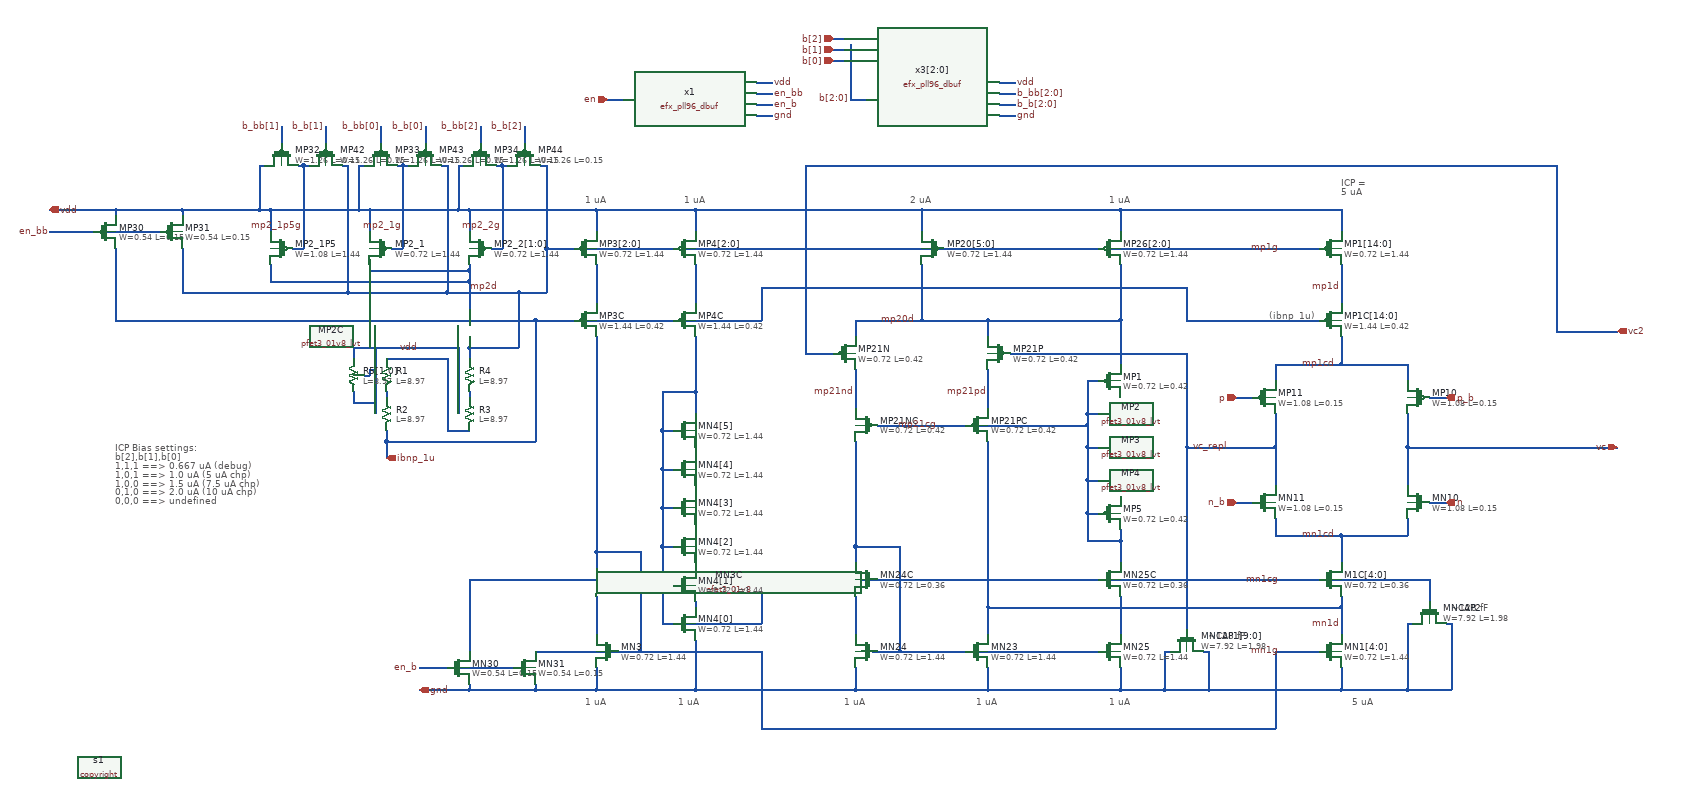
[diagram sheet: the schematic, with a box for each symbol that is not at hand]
v {xschem version=3.4.7 file_version=1.2}
G {}
K {}
V {}
S {}
E {}
T {ICP =
5 uA} 2250 -1060 0 1 0.4 0.4 {hcenter=true}
T {1 uA} 880 -120 0 0 0.4 0.4 {}
T {5 uA} 2270 -120 0 1 0.4 0.4 {}
T {ICP Bias settings:
b[2],b[1],b[0]
1,1,1 ==> 0.667 uA (debug)
1,0,1 ==> 1.0 uA (5 uA chp)
1,0,0 ==> 1.5 uA (7.5 uA chp)
0,1,0 ==> 2.0 uA (10 uA chp)
0,0,0 ==> undefined} 30 -580 0 0 0.4 0.4 {}
T {2 uA} 1470 -1030 0 0 0.4 0.4 {}
T {1 uA} 1590 -120 0 0 0.4 0.4 {}
T {1 uA} 1350 -120 0 0 0.4 0.4 {}
T {1 uA} 880 -1030 0 0 0.4 0.4 {}
T {(ibnp_1u)} 2120 -820 0 0 0.3 0.3 {hcenter=true}
T {1 uA} 1060 -1030 0 0 0.4 0.4 {}
T {1 uA} 1050 -120 0 0 0.4 0.4 {}
T {1 uA} 1830 -120 0 0 0.4 0.4 {}
T {1 uA} 1830 -1030 0 0 0.4 0.4 {}
T {~128 fF} 2010 -240 0 0 0.3 0.3 {}
T {~128 fF} 2450 -290 0 0 0.3 0.3 {}
N 900 -170 900 -130 {lab=gnd}
N 900 -300 900 -230 {lab=#net1}
N 2250 -900 2250 -830 {lab=mp1d}
N 2250 -1000 2250 -960 {lab=vdd}
N 2250 -170 2250 -130 {lab=gnd}
N 2250 -280 2250 -230 {lab=mn1d}
N 2250 -770 2250 -720 {lab=mp1cd}
N 2250 -410 2250 -360 {lab=mn1cd}
N 2130 -410 2250 -410 {lab=mn1cd}
N 2250 -410 2370 -410 {lab=mn1cd}
N 2250 -720 2370 -720 {lab=mp1cd}
N 2130 -720 2250 -720 {lab=mp1cd}
N 2130 -720 2130 -690 {lab=mp1cd}
N 2130 -440 2130 -410 {lab=mn1cd}
N 2370 -440 2370 -410 {lab=mn1cd}
N 2370 -720 2370 -690 {lab=mp1cd}
N 2410 -470 2440 -470 {lab=n}
N 2060 -660 2090 -660 {lab=p}
N 2060 -470 2090 -470 {lab=n_b}
N 1490 -1000 1490 -960 {
lab=vdd}
N 920 -1200 950 -1200 {
lab=en}
N 670 -140 670 -130 {
lab=gnd}
N 150 -1000 150 -990 {
lab=vdd}
N 30 -1000 30 -990 {
lab=vdd}
N 2410 -660 2440 -660 {
lab=p_b}
N 790 -140 790 -130 {
lab=gnd}
N 1610 -800 1610 -770 {lab=mp20d}
N 1370 -800 1370 -770 {lab=mp20d}
N 1370 -800 1490 -800 {lab=mp20d}
N 1490 -900 1490 -800 {
lab=mp20d}
N 1610 -170 1610 -130 {
lab=gnd}
N 1370 -170 1370 -130 {
lab=gnd}
N 1370 -300 1370 -230 {
lab=#net2}
N 1370 -390 1450 -390 {
lab=#net3}
N 1450 -390 1450 -200 {
lab=#net3}
N 900 -380 900 -350 {lab=mn1g}
N 670 -130 790 -130 {
lab=gnd}
N 1280 -740 1330 -740 {
lab=vc2}
N 670 -1000 670 -960 {lab=vdd}
N 490 -1000 490 -960 {lab=vdd}
N 470 -1080 470 -1000 {
lab=vdd}
N 550 -1080 560 -1080 {
lab=mp2_1g}
N 550 -1080 550 -930 {
lab=mp2_1g}
N 530 -930 550 -930 {
lab=mp2_1g}
N 630 -1080 630 -850 {
lab=mp1g}
N 620 -1080 630 -1080 {
lab=mp1g}
N 470 -1080 480 -1080 {
lab=vdd}
N 310 -1000 310 -960 {lab=vdd}
N 290 -1080 290 -1000 {
lab=vdd}
N 370 -1080 380 -1080 {
lab=mp2_1p5g}
N 370 -1080 370 -930 {
lab=mp2_1p5g}
N 350 -930 370 -930 {
lab=mp2_1p5g}
N 440 -1080 450 -1080 {
lab=mp1g}
N 290 -1080 300 -1080 {
lab=vdd}
N 470 -1000 490 -1000 {
lab=vdd}
N 310 -900 310 -870 {
lab=mp2d}
N 710 -930 730 -930 {
lab=mp2_2g}
N 540 -1080 550 -1080 {
lab=mp2_1g}
N 290 -1000 310 -1000 {
lab=vdd}
N 360 -1080 370 -1080 {
lab=mp2_1p5g}
N 900 -1000 900 -960 {
lab=vdd}
N 900 -900 900 -830 {
lab=#net4}
N 150 -1000 290 -1000 {
lab=vdd}
N 580 -130 670 -130 {
lab=gnd}
N 670 -330 670 -200 {
lab=mn1cg}
N 580 -170 750 -170 {
lab=en_b}
N 30 -1000 150 -1000 {
lab=vdd}
N -90 -1000 30 -1000 {
lab=vdd}
N -90 -960 110 -960 {
lab=en_bb}
N 330 -1150 330 -1120 {
lab=b_bb[1]}
N 410 -1150 410 -1120 {
lab=b_b[1]}
N 510 -1150 510 -1120 {
lab=b_bb[0]}
N 590 -1150 590 -1120 {
lab=b_b[0]}
N 1190 -1230 1220 -1230 {
lab=vdd}
N 1190 -1210 1220 -1210 {
lab=en_bb}
N 1190 -1190 1220 -1190 {
lab=en_b}
N 1190 -1170 1220 -1170 {
lab=gnd}
N 1360 -1200 1390 -1200 {
lab=b[2:0]}
N 1630 -1230 1660 -1230 {
lab=vdd}
N 1630 -1210 1660 -1210 {
lab=b_bb[2:0]}
N 1630 -1190 1660 -1190 {
lab=b_b[2:0]}
N 1630 -1170 1660 -1170 {
lab=gnd}
N 670 -770 670 -750 {
lab=mp1g}
N 760 -850 760 -750 {
lab=mp1g}
N 30 -930 30 -800 {
lab=ibnp_1u}
N 670 -750 670 -730 {
lab=mp1g}
N 900 -380 980 -380 {
lab=mn1g}
N 980 -380 980 -200 {
lab=mn1g}
N 790 -130 900 -130 {
lab=gnd}
N 310 -1000 470 -1000 {
lab=vdd}
N 670 -750 760 -750 {
lab=mp1g}
N 650 -1000 670 -1000 {
lab=vdd}
N 670 -870 670 -820 {
lab=mp2d}
N 450 -850 630 -850 {
lab=mp1g}
N 150 -850 450 -850 {
lab=mp1g}
N 450 -1080 450 -850 {
lab=mp1g}
N 490 -910 490 -890 {
lab=mp2d}
N 490 -890 670 -890 {
lab=mp2d}
N 670 -900 670 -890 {
lab=mp2d}
N 310 -870 670 -870 {
lab=mp2d}
N 670 -890 670 -870 {
lab=mp2d}
N 150 -930 150 -850 {
lab=mp1g}
N 670 -670 670 -660 {
lab=#net5}
N 520 -670 520 -660 {
lab=#net6}
N 520 -730 630 -730 {
lab=#net7}
N 650 -750 650 -630 {
lab=vdd}
N 500 -650 500 -630 {
lab=vdd}
N 630 -600 670 -600 {
lab=#net7}
N 520 -580 790 -580 {
lab=ibnp_1u}
N 520 -580 520 -550 {
lab=ibnp_1u}
N 460 -750 460 -730 {
lab=vdd}
N 500 -750 650 -750 {
lab=vdd}
N 460 -750 500 -750 {
lab=vdd}
N 500 -710 500 -650 {
lab=vdd}
N 460 -670 460 -650 {
lab=vdd}
N 460 -650 500 -650 {
lab=vdd}
N 630 -730 630 -600 {
lab=#net7}
N 520 -600 520 -580 {
lab=ibnp_1u}
N 790 -800 790 -580 {
lab=ibnp_1u}
N 650 -1080 650 -1000 {
lab=vdd}
N 730 -1080 740 -1080 {
lab=mp2_2g}
N 730 -1080 730 -930 {
lab=mp2_2g}
N 800 -1080 810 -1080 {
lab=mp1g}
N 650 -1080 660 -1080 {
lab=vdd}
N 720 -1080 730 -1080 {
lab=mp2_2g}
N 690 -1150 690 -1120 {
lab=b_bb[2]}
N 770 -1150 770 -1120 {
lab=b_b[2]}
N 490 -1000 650 -1000 {
lab=vdd}
N 630 -850 760 -850 {
lab=mp1g}
N 810 -930 810 -850 {
lab=mp1g}
N 810 -1080 810 -930 {
lab=mp1g}
N 760 -850 810 -850 {
lab=mp1g}
N 30 -800 790 -800 {
lab=ibnp_1u}
N 1330 -1310 1350 -1310 {
lab=b[2]}
N 1330 -1290 1350 -1290 {
lab=b[1]}
N 1330 -1270 1350 -1270 {
lab=b[0]}
N 1360 -1300 1360 -1200 {
lab=b[2:0]}
N 480 -700 490 -700 {
lab=vdd}
N 490 -710 490 -700 {
lab=vdd}
N 490 -710 500 -710 {
lab=vdd}
N 500 -750 500 -710 {
lab=vdd}
N 900 -770 900 -380 {
lab=mn1g}
N 1080 -1000 1080 -960 {
lab=vdd}
N 1080 -900 1080 -830 {
lab=#net8}
N 900 -1000 1080 -1000 {
lab=vdd}
N 670 -1000 900 -1000 {
lab=vdd}
N 1020 -320 1020 -250 {
lab=mn1cg}
N 1020 -460 1040 -460 {
lab=mn1cg}
N 1020 -390 1040 -390 {
lab=mn1cg}
N 1020 -460 1020 -390 {
lab=mn1cg}
N 1020 -320 1040 -320 {
lab=mn1cg}
N 1020 -390 1020 -320 {
lab=mn1cg}
N 1080 -430 1080 -420 {
lab=#net9}
N 1080 -360 1080 -350 {
lab=#net10}
N 1080 -290 1080 -280 {
lab=#net11}
N 1020 -530 1040 -530 {
lab=mn1cg}
N 1080 -500 1080 -490 {
lab=#net12}
N 1020 -530 1020 -460 {
lab=mn1cg}
N 2370 -570 2370 -500 {lab=vc}
N 2370 -630 2370 -570 {lab=vc}
N 2370 -570 2750 -570 {
lab=vc}
N 2130 -200 2210 -200 {
lab=mn1g}
N 790 -800 1200 -800 {
lab=ibnp_1u}
N 1200 -860 1200 -800 {
lab=ibnp_1u}
N 1370 -390 1370 -360 {
lab=#net3}
N 1200 -860 1970 -860 {
lab=ibnp_1u}
N 1850 -800 1850 -720 {lab=mp20d}
N 1080 -1000 1490 -1000 {
lab=vdd}
N 1850 -1000 1850 -960 {
lab=vdd}
N 1490 -1000 1850 -1000 {
lab=vdd}
N 1370 -130 1610 -130 {
lab=gnd}
N 1850 -170 1850 -130 {
lab=gnd}
N 1850 -300 1850 -230 {
lab=#net13}
N 1400 -200 1450 -200 {
lab=#net3}
N 790 -200 980 -200 {
lab=mn1g}
N 980 -200 1200 -200 {
lab=mn1g}
N 1490 -800 1610 -800 {
lab=mp20d}
N 1200 -200 1200 -60 {
lab=mn1g}
N 2130 -200 2130 -60 {
lab=mn1g}
N 1020 -600 1040 -600 {
lab=mn1cg}
N 1080 -570 1080 -560 {
lab=#net14}
N 1020 -600 1020 -530 {
lab=mn1cg}
N 1080 -670 1080 -620 {
lab=mn1cg}
N 1080 -220 1080 -130 {
lab=gnd}
N 900 -130 1080 -130 {
lab=gnd}
N 1020 -670 1020 -600 {
lab=mn1cg}
N 1020 -670 1080 -670 {
lab=mn1cg}
N 1080 -770 1080 -670 {
lab=mn1cg}
N 1020 -250 1200 -250 {
lab=mn1cg}
N 1200 -330 1200 -250 {
lab=mn1cg}
N 670 -330 1200 -330 {
lab=mn1cg}
N 810 -930 2210 -930 {
lab=mp1g}
N 2130 -570 2130 -500 {
lab=vc_repl}
N 1200 -60 2130 -60 {
lab=mn1g}
N 1930 -200 1940 -200 {
lab=gnd}
N 2000 -200 2010 -200 {
lab=gnd}
N 1930 -130 2010 -130 {
lab=gnd}
N 2370 -250 2380 -250 {
lab=gnd}
N 2370 -250 2370 -130 {
lab=gnd}
N 2440 -250 2450 -250 {
lab=gnd}
N 2450 -250 2450 -130 {
lab=gnd}
N 2370 -130 2450 -130 {
lab=gnd}
N 2410 -330 2410 -290 {
lab=mn1cg}
N 2250 -130 2370 -130 {
lab=gnd}
N 2010 -130 2250 -130 {
lab=gnd}
N 1970 -800 2210 -800 {
lab=ibnp_1u}
N 1970 -570 2130 -570 {
lab=vc_repl}
N 2130 -630 2130 -570 {
lab=vc_repl}
N 1080 -130 1370 -130 {
lab=gnd}
N 2640 -1080 2640 -780 {lab=vc2}
N 2640 -780 2750 -780 {lab=vc2}
N 1610 -130 1850 -130 {
lab=gnd}
N 1970 -740 1970 -570 {lab=vc_repl}
N 1280 -1080 1280 -740 {lab=vc2}
N 1280 -1080 2640 -1080 {lab=vc2}
N 1610 -280 2250 -280 {lab=mn1d}
N 1610 -280 1610 -230 {lab=mn1d}
N 2250 -300 2250 -280 {lab=mn1d}
N 1790 -450 1790 -400 {lab=mp21cg}
N 1850 -420 1850 -400 {lab=mp21cg}
N 1200 -330 2410 -330 {
lab=mn1cg}
N 1850 -1000 2250 -1000 {
lab=vdd}
N 1850 -130 1930 -130 {
lab=gnd}
N 1790 -400 1850 -400 {lab=mp21cg}
N 1790 -690 1810 -690 {lab=mp21cg}
N 1790 -630 1810 -630 {lab=mp21cg}
N 1790 -690 1790 -630 {lab=mp21cg}
N 1790 -570 1810 -570 {lab=mp21cg}
N 1790 -610 1790 -570 {lab=mp21cg}
N 1790 -510 1810 -510 {lab=mp21cg}
N 1790 -570 1790 -510 {lab=mp21cg}
N 1790 -450 1810 -450 {lab=mp21cg}
N 1790 -510 1790 -450 {lab=mp21cg}
N 1650 -740 1970 -740 {
lab=vc_repl}
N 1450 -200 1810 -200 {
lab=#net3}
N 1850 -400 1850 -360 {lab=mp21cg}
N 1930 -200 1930 -130 {
lab=gnd}
N 2010 -200 2010 -130 {
lab=gnd}
N 1970 -570 1970 -240 {lab=vc_repl}
N 1970 -860 1970 -800 {lab=ibnp_1u}
N 1610 -800 1850 -800 {lab=mp20d}
N 1850 -900 1850 -800 {lab=mp20d}
N 1370 -710 1370 -640 {
lab=mp21nd}
N 1610 -710 1610 -640 {
lab=mp21pd}
N 1370 -580 1370 -390 {lab=#net3}
N 1610 -580 1610 -280 {lab=mn1d}
N 1790 -630 1790 -610 {lab=mp21cg}
N 1410 -610 1790 -610 {lab=mp21cg}
C {title_efx.sym} 200 -40 0 0 {name=l1 author="ejfogleman"}
C {iopin.sym} -90 -1000 0 1 {name=p1 lab=vdd}
C {iopin.sym} 580 -130 0 1 {name=p2 lab=gnd}
C {iopin.sym} 520 -550 3 1 {name=p3 lab=ibnp_1u
}
C {sky130_fd_pr/pfet3_01v8_lvt.sym} 690 -930 0 1 {name=MP2_2[1:0]
W=0.72
L=1.44
body=vdd
nf=1
mult=1
ad="'int((nf+1)/2) * W/nf * 0.29'" 
pd="'2*int((nf+1)/2) * (W/nf + 0.29)'"
as="'int((nf+2)/2) * W/nf * 0.29'" 
ps="'2*int((nf+2)/2) * (W/nf + 0.29)'"
nrd="'0.29 / W'" nrs="'0.29 / W'"
sa=0 sb=0 sd=0
model=pfet_01v8_lvt
spiceprefix=X
}
C {sky130_fd_pr/nfet3_01v8.sym} 920 -200 0 1 {name=MN3
W=0.72
L=1.44
body=gnd
nf=1
mult=1
ad="'int((nf+1)/2) * W/nf * 0.29'" 
pd="'2*int((nf+1)/2) * (W/nf + 0.29)'"
as="'int((nf+2)/2) * W/nf * 0.29'" 
ps="'2*int((nf+2)/2) * (W/nf + 0.29)'"
nrd="'0.29 / W'" nrs="'0.29 / W'"
sa=0 sb=0 sd=0
model=nfet_01v8
spiceprefix=X
}
C {sky130_fd_pr/nfet3_01v8.sym} 920 -330 0 1 {name=MN3C
W=0.72
L=0.36
body=gnd
nf=1
mult=1
ad="'int((nf+1)/2) * W/nf * 0.29'" 
pd="'2*int((nf+1)/2) * (W/nf + 0.29)'"
as="'int((nf+2)/2) * W/nf * 0.29'" 
ps="'2*int((nf+2)/2) * (W/nf + 0.29)'"
nrd="'0.29 / W'" nrs="'0.29 / W'"
sa=0 sb=0 sd=0
model=nfet_01v8
spiceprefix=X
}
C {sky130_fd_pr/pfet3_01v8_lvt.sym} 2230 -930 0 0 {name=MP1[14:0]
W=0.72
L=1.44
body=vdd
nf=1
mult=1
ad="'int((nf+1)/2) * W/nf * 0.29'" 
pd="'2*int((nf+1)/2) * (W/nf + 0.29)'"
as="'int((nf+2)/2) * W/nf * 0.29'" 
ps="'2*int((nf+2)/2) * (W/nf + 0.29)'"
nrd="'0.29 / W'" nrs="'0.29 / W'"
sa=0 sb=0 sd=0
model=pfet_01v8_lvt
spiceprefix=X
}
C {sky130_fd_pr/pfet3_01v8_lvt.sym} 690 -800 0 1 {name=MP2C
W=1.44
L=0.42
body=vdd
nf=2
mult=1
ad="'int((nf+1)/2) * W/nf * 0.29'" 
pd="'2*int((nf+1)/2) * (W/nf + 0.29)'"
as="'int((nf+2)/2) * W/nf * 0.29'" 
ps="'2*int((nf+2)/2) * (W/nf + 0.29)'"
nrd="'0.29 / W'" nrs="'0.29 / W'"
sa=0 sb=0 sd=0
model=pfet_01v8_lvt
spiceprefix=X
}
C {sky130_fd_pr/pfet3_01v8_lvt.sym} 2230 -800 0 0 {name=MP1C[14:0]
W=1.44
L=0.42
body=vdd
nf=2
mult=1
ad="'int((nf+1)/2) * W/nf * 0.29'" 
pd="'2*int((nf+1)/2) * (W/nf + 0.29)'"
as="'int((nf+2)/2) * W/nf * 0.29'" 
ps="'2*int((nf+2)/2) * (W/nf + 0.29)'"
nrd="'0.29 / W'" nrs="'0.29 / W'"
sa=0 sb=0 sd=0
model=pfet_01v8_lvt
spiceprefix=X
}
C {sky130_fd_pr/nfet3_01v8.sym} 2230 -200 0 0 {name=MN1[4:0]
W=0.72
L=1.44
body=gnd
nf=1
mult=1
ad="'int((nf+1)/2) * W/nf * 0.29'" 
pd="'2*int((nf+1)/2) * (W/nf + 0.29)'"
as="'int((nf+2)/2) * W/nf * 0.29'" 
ps="'2*int((nf+2)/2) * (W/nf + 0.29)'"
nrd="'0.29 / W'" nrs="'0.29 / W'"
sa=0 sb=0 sd=0
model=nfet_01v8
spiceprefix=X
}
C {sky130_fd_pr/nfet3_01v8.sym} 2230 -330 0 0 {name=M1C[4:0]
W=0.72
L=0.36
body=gnd
nf=1	
mult=1
ad="'int((nf+1)/2) * W/nf * 0.29'" 
pd="'2*int((nf+1)/2) * (W/nf + 0.29)'"
as="'int((nf+2)/2) * W/nf * 0.29'" 
ps="'2*int((nf+2)/2) * (W/nf + 0.29)'"
nrd="'0.29 / W'" nrs="'0.29 / W'"
sa=0 sb=0 sd=0
model=nfet_01v8
spiceprefix=X
}
C {sky130_fd_pr/pfet3_01v8.sym} 2110 -660 0 0 {name=MP11
W=1.08
L=0.15
body=vdd
nf=1
mult=1
ad="'int((nf+1)/2) * W/nf * 0.29'" 
pd="'2*int((nf+1)/2) * (W/nf + 0.29)'"
as="'int((nf+2)/2) * W/nf * 0.29'" 
ps="'2*int((nf+2)/2) * (W/nf + 0.29)'"
nrd="'0.29 / W'" nrs="'0.29 / W'"
sa=0 sb=0 sd=0
model=pfet_01v8
spiceprefix=X
}
C {sky130_fd_pr/nfet3_01v8.sym} 2110 -470 0 0 {name=MN11
W=1.08
L=0.15
body=gnd
nf=1
mult=1
ad="'int((nf+1)/2) * W/nf * 0.29'" 
pd="'2*int((nf+1)/2) * (W/nf + 0.29)'"
as="'int((nf+2)/2) * W/nf * 0.29'" 
ps="'2*int((nf+2)/2) * (W/nf + 0.29)'"
nrd="'0.29 / W'" nrs="'0.29 / W'"
sa=0 sb=0 sd=0
model=nfet_01v8
spiceprefix=X
}
C {sky130_fd_pr/pfet3_01v8.sym} 2390 -660 0 1 {name=MP10
W=1.08
L=0.15
body=vdd
nf=1
mult=1
ad="'int((nf+1)/2) * W/nf * 0.29'" 
pd="'2*int((nf+1)/2) * (W/nf + 0.29)'"
as="'int((nf+2)/2) * W/nf * 0.29'" 
ps="'2*int((nf+2)/2) * (W/nf + 0.29)'"
nrd="'0.29 / W'" nrs="'0.29 / W'"
sa=0 sb=0 sd=0
model=pfet_01v8
spiceprefix=X
}
C {sky130_fd_pr/nfet3_01v8.sym} 2390 -470 0 1 {name=MN10
W=1.08
L=0.15
body=gnd
nf=1
mult=1
ad="'int((nf+1)/2) * W/nf * 0.29'" 
pd="'2*int((nf+1)/2) * (W/nf + 0.29)'"
as="'int((nf+2)/2) * W/nf * 0.29'" 
ps="'2*int((nf+2)/2) * (W/nf + 0.29)'"
nrd="'0.29 / W'" nrs="'0.29 / W'"
sa=0 sb=0 sd=0
model=nfet_01v8
spiceprefix=X
}
C {iopin.sym} 2750 -570 0 0 {name=p11 lab=vc}
C {ipin.sym} 2060 -660 0 0 {name=p12 lab=p}
C {ipin.sym} 2060 -470 0 0 {name=p13 lab=n_b}
C {ipin.sym} 2440 -660 0 1 {name=p14 lab=p_b}
C {ipin.sym} 2440 -470 0 1 {name=p15 lab=n}
C {lab_wire.sym} 2140 -930 0 0 {name=p16 sig_type=std_logic lab=mp1g}
C {lab_wire.sym} 2140 -200 0 0 {name=p18 sig_type=std_logic lab=mn1g}
C {lab_wire.sym} 2240 -720 0 0 {name=p19 sig_type=std_logic lab=mp1cd}
C {lab_wire.sym} 2240 -410 0 0 {name=p20 sig_type=std_logic lab=mn1cd}
C {lab_wire.sym} 2250 -860 0 0 {name=p21 sig_type=std_logic lab=mp1d}
C {lab_wire.sym} 2250 -250 0 0 {name=p22 sig_type=std_logic lab=mn1d}
C {sky130_fd_pr/pfet3_01v8_lvt.sym} 1510 -930 0 1 {name=MP20[5:0]
W=0.72
L=1.44
body=vdd
nf=1
mult=1
ad="'int((nf+1)/2) * W/nf * 0.29'" 
pd="'2*int((nf+1)/2) * (W/nf + 0.29)'"
as="'int((nf+2)/2) * W/nf * 0.29'" 
ps="'2*int((nf+2)/2) * (W/nf + 0.29)'"
nrd="'0.29 / W'" nrs="'0.29 / W'"
sa=0 sb=0 sd=0
model=pfet_01v8_lvt
spiceprefix=X
}
C {lab_wire.sym} 1980 -570 0 1 {name=p5 sig_type=std_logic lab=vc_repl}
C {ipin.sym} 920 -1200 0 0 {name=p26 lab=en}
C {ipin.sym} 1330 -1310 0 0 {name=p28 lab=b[2]}
C {lab_pin.sym} 580 -170 0 0 {name=p40 sig_type=std_logic lab=en_b}
C {sky130_fd_pr/nfet3_01v8.sym} 650 -170 0 0 {name=MN30
W=0.54
L=0.15
body=gnd
nf=1
mult=1
ad="'int((nf+1)/2) * W/nf * 0.29'" 
pd="'2*int((nf+1)/2) * (W/nf + 0.29)'"
as="'int((nf+2)/2) * W/nf * 0.29'" 
ps="'2*int((nf+2)/2) * (W/nf + 0.29)'"
nrd="'0.29 / W'" nrs="'0.29 / W'"
sa=0 sb=0 sd=0
model=nfet_01v8
spiceprefix=X
}
C {lab_pin.sym} -90 -960 0 0 {name=p41 sig_type=std_logic lab=en_bb}
C {lab_wire.sym} 670 -860 0 1 {name=p4 sig_type=std_logic lab=mp2d}
C {sky130_fd_pr/nfet3_01v8.sym} 770 -170 0 0 {name=MN31
W=0.54
L=0.15
body=gnd
nf=1
mult=1
ad="'int((nf+1)/2) * W/nf * 0.29'" 
pd="'2*int((nf+1)/2) * (W/nf + 0.29)'"
as="'int((nf+2)/2) * W/nf * 0.29'" 
ps="'2*int((nf+2)/2) * (W/nf + 0.29)'"
nrd="'0.29 / W'" nrs="'0.29 / W'"
sa=0 sb=0 sd=0
model=nfet_01v8
spiceprefix=X
}
C {sky130_fd_pr/pfet3_01v8_lvt.sym} 1630 -740 0 1 {name=MP21P
W=0.72
L=0.42
body=vdd
nf=1
mult=1
ad="'int((nf+1)/2) * W/nf * 0.29'" 
pd="'2*int((nf+1)/2) * (W/nf + 0.29)'"
as="'int((nf+2)/2) * W/nf * 0.29'" 
ps="'2*int((nf+2)/2) * (W/nf + 0.29)'"
nrd="'0.29 / W'" nrs="'0.29 / W'"
sa=0 sb=0 sd=0
model=pfet_01v8_lvt
spiceprefix=X
}
C {sky130_fd_pr/pfet3_01v8_lvt.sym} 1350 -740 0 0 {name=MP21N
W=0.72
L=0.42
body=vdd
nf=1
mult=1
ad="'int((nf+1)/2) * W/nf * 0.29'" 
pd="'2*int((nf+1)/2) * (W/nf + 0.29)'"
as="'int((nf+2)/2) * W/nf * 0.29'" 
ps="'2*int((nf+2)/2) * (W/nf + 0.29)'"
nrd="'0.29 / W'" nrs="'0.29 / W'"
sa=0 sb=0 sd=0
model=pfet_01v8_lvt
spiceprefix=X
}
C {sky130_fd_pr/nfet3_01v8.sym} 1390 -200 0 1 {name=MN24
W=0.72
L=1.44
body=gnd
nf=1
mult=1
ad="'int((nf+1)/2) * W/nf * 0.29'" 
pd="'2*int((nf+1)/2) * (W/nf + 0.29)'"
as="'int((nf+2)/2) * W/nf * 0.29'" 
ps="'2*int((nf+2)/2) * (W/nf + 0.29)'"
nrd="'0.29 / W'" nrs="'0.29 / W'"
sa=0 sb=0 sd=0
model=nfet_01v8
spiceprefix=X
}
C {sky130_fd_pr/nfet3_01v8.sym} 1590 -200 0 0 {name=MN23
W=0.72
L=1.44
body=gnd
nf=1
mult=1
ad="'int((nf+1)/2) * W/nf * 0.29'" 
pd="'2*int((nf+1)/2) * (W/nf + 0.29)'"
as="'int((nf+2)/2) * W/nf * 0.29'" 
ps="'2*int((nf+2)/2) * (W/nf + 0.29)'"
nrd="'0.29 / W'" nrs="'0.29 / W'"
sa=0 sb=0 sd=0
model=nfet_01v8
spiceprefix=X
}
C {sky130_fd_pr/nfet3_01v8.sym} 1390 -330 0 1 {name=MN24C
W=0.72
L=0.36
body=gnd
nf=1
mult=1
ad="'int((nf+1)/2) * W/nf * 0.29'" 
pd="'2*int((nf+1)/2) * (W/nf + 0.29)'"
as="'int((nf+2)/2) * W/nf * 0.29'" 
ps="'2*int((nf+2)/2) * (W/nf + 0.29)'"
nrd="'0.29 / W'" nrs="'0.29 / W'"
sa=0 sb=0 sd=0
model=nfet_01v8
spiceprefix=X
}
C {sky130_fd_pr/pfet3_01v8_lvt.sym} 510 -930 0 1 {name=MP2_1
W=0.72
L=1.44
body=vdd
nf=1
mult=1
ad="'int((nf+1)/2) * W/nf * 0.29'" 
pd="'2*int((nf+1)/2) * (W/nf + 0.29)'"
as="'int((nf+2)/2) * W/nf * 0.29'" 
ps="'2*int((nf+2)/2) * (W/nf + 0.29)'"
nrd="'0.29 / W'" nrs="'0.29 / W'"
sa=0 sb=0 sd=0
model=pfet_01v8_lvt
spiceprefix=X
}
C {sky130_fd_pr/pfet3_01v8_lvt.sym} 330 -930 0 1 {name=MP2_1P5
W=1.08
L=1.44
body=vdd
nf=1
mult=1
ad="'int((nf+1)/2) * W/nf * 0.29'" 
pd="'2*int((nf+1)/2) * (W/nf + 0.29)'"
as="'int((nf+2)/2) * W/nf * 0.29'" 
ps="'2*int((nf+2)/2) * (W/nf + 0.29)'"
nrd="'0.29 / W'" nrs="'0.29 / W'"
sa=0 sb=0 sd=0
model=pfet_01v8_lvt
spiceprefix=X
}
C {sky130_fd_pr/pfet3_01v8_hvt.sym} 330 -1100 3 1 {name=MP32
W=1.26
L=0.15
body=vdd
nf=1
mult=1
ad="'int((nf+1)/2) * W/nf * 0.29'" 
pd="'2*int((nf+1)/2) * (W/nf + 0.29)'"
as="'int((nf+2)/2) * W/nf * 0.29'" 
ps="'2*int((nf+2)/2) * (W/nf + 0.29)'"
nrd="'0.29 / W'" nrs="'0.29 / W'"
sa=0 sb=0 sd=0
model=pfet_01v8_hvt
spiceprefix=X
}
C {sky130_fd_pr/pfet3_01v8_lvt.sym} 880 -800 0 0 {name=MP3C
W=1.44
L=0.42
body=vdd
nf=2
mult=1
ad="'int((nf+1)/2) * W/nf * 0.29'" 
pd="'2*int((nf+1)/2) * (W/nf + 0.29)'"
as="'int((nf+2)/2) * W/nf * 0.29'" 
ps="'2*int((nf+2)/2) * (W/nf + 0.29)'"
nrd="'0.29 / W'" nrs="'0.29 / W'"
sa=0 sb=0 sd=0
model=pfet_01v8_lvt
spiceprefix=X
}
C {sky130_fd_pr/pfet3_01v8_lvt.sym} 880 -930 0 0 {name=MP3[2:0]
W=0.72
L=1.44
body=vdd
nf=1
mult=1
ad="'int((nf+1)/2) * W/nf * 0.29'" 
pd="'2*int((nf+1)/2) * (W/nf + 0.29)'"
as="'int((nf+2)/2) * W/nf * 0.29'" 
ps="'2*int((nf+2)/2) * (W/nf + 0.29)'"
nrd="'0.29 / W'" nrs="'0.29 / W'"
sa=0 sb=0 sd=0
model=pfet_01v8_lvt
spiceprefix=X
}
C {lab_pin.sym} 330 -1150 1 0 {name=p6 sig_type=std_logic lab=b_bb[1]}
C {lab_pin.sym} 410 -1150 1 0 {name=p9 sig_type=std_logic lab=b_b[1]
}
C {lab_pin.sym} 510 -1150 1 0 {name=p24 sig_type=std_logic lab=b_bb[0]}
C {lab_pin.sym} 590 -1150 1 0 {name=p43 sig_type=std_logic lab=b_b[0]}
C {efx_pll96_dbuf.sym} 1070 -1200 0 0 {name=x1}
C {lab_pin.sym} 1220 -1230 0 1 {name=p10 sig_type=std_logic lab=vdd}
C {lab_pin.sym} 1220 -1170 0 1 {name=p57 sig_type=std_logic lab=gnd}
C {lab_pin.sym} 1220 -1210 0 1 {name=p58 sig_type=std_logic lab=en_bb}
C {lab_pin.sym} 1220 -1190 0 1 {name=p59 sig_type=std_logic lab=en_b}
C {efx_pll96_dbuf.sym} 1510 -1200 0 0 {name=x3[2:0]}
C {lab_pin.sym} 1660 -1230 0 1 {name=p64 sig_type=std_logic lab=vdd}
C {lab_pin.sym} 1660 -1170 0 1 {name=p65 sig_type=std_logic lab=gnd}
C {lab_pin.sym} 1660 -1210 0 1 {name=p66 sig_type=std_logic lab=b_bb[2:0]}
C {lab_pin.sym} 1660 -1190 0 1 {name=p67 sig_type=std_logic lab=b_b[2:0]}
C {lab_wire.sym} 2140 -330 0 0 {name=p17 sig_type=std_logic lab=mn1cg}
C {lab_wire.sym} 580 -750 0 0 {name=p23 sig_type=std_logic lab=vdd}
C {sky130_fd_pr/pfet3_01v8_hvt.sym} 410 -1100 3 1 {name=MP42
W=1.26
L=0.15
body=vdd
nf=1
mult=1
ad="'int((nf+1)/2) * W/nf * 0.29'" 
pd="'2*int((nf+1)/2) * (W/nf + 0.29)'"
as="'int((nf+2)/2) * W/nf * 0.29'" 
ps="'2*int((nf+2)/2) * (W/nf + 0.29)'"
nrd="'0.29 / W'" nrs="'0.29 / W'"
sa=0 sb=0 sd=0
model=pfet_01v8_hvt
spiceprefix=X
}
C {sky130_fd_pr/pfet3_01v8_hvt.sym} 510 -1100 3 1 {name=MP33
W=1.26
L=0.15
body=vdd
nf=1
mult=1
ad="'int((nf+1)/2) * W/nf * 0.29'" 
pd="'2*int((nf+1)/2) * (W/nf + 0.29)'"
as="'int((nf+2)/2) * W/nf * 0.29'" 
ps="'2*int((nf+2)/2) * (W/nf + 0.29)'"
nrd="'0.29 / W'" nrs="'0.29 / W'"
sa=0 sb=0 sd=0
model=pfet_01v8_hvt
spiceprefix=X
}
C {sky130_fd_pr/pfet3_01v8_hvt.sym} 590 -1100 3 1 {name=MP43
W=1.26
L=0.15
body=vdd
nf=1
mult=1
ad="'int((nf+1)/2) * W/nf * 0.29'" 
pd="'2*int((nf+1)/2) * (W/nf + 0.29)'"
as="'int((nf+2)/2) * W/nf * 0.29'" 
ps="'2*int((nf+2)/2) * (W/nf + 0.29)'"
nrd="'0.29 / W'" nrs="'0.29 / W'"
sa=0 sb=0 sd=0
model=pfet_01v8_hvt
spiceprefix=X
}
C {sky130_fd_pr/pfet3_01v8_hvt.sym} 10 -960 0 0 {name=MP30
W=0.54
L=0.15
body=vdd
nf=1
mult=1
ad="'int((nf+1)/2) * W/nf * 0.29'" 
pd="'2*int((nf+1)/2) * (W/nf + 0.29)'"
as="'int((nf+2)/2) * W/nf * 0.29'" 
ps="'2*int((nf+2)/2) * (W/nf + 0.29)'"
nrd="'0.29 / W'" nrs="'0.29 / W'"
sa=0 sb=0 sd=0
model=pfet_01v8_hvt
spiceprefix=X
}
C {sky130_fd_pr/pfet3_01v8_hvt.sym} 130 -960 0 0 {name=MP31
W=0.54
L=0.15
body=vdd
nf=1
mult=1
ad="'int((nf+1)/2) * W/nf * 0.29'" 
pd="'2*int((nf+1)/2) * (W/nf + 0.29)'"
as="'int((nf+2)/2) * W/nf * 0.29'" 
ps="'2*int((nf+2)/2) * (W/nf + 0.29)'"
nrd="'0.29 / W'" nrs="'0.29 / W'"
sa=0 sb=0 sd=0
model=pfet_01v8_hvt
spiceprefix=X
}
C {sky130_fd_pr/res_xhigh_po_0p69.sym} 460 -700 0 1 {name=R5[1:0]
L=8.97
model=res_xhigh_po_0p69
spiceprefix=X
mult=1}
C {lab_pin.sym} 690 -1150 1 0 {name=p27 sig_type=std_logic lab=b_bb[2]}
C {lab_pin.sym} 770 -1150 1 0 {name=p30 sig_type=std_logic lab=b_b[2]}
C {sky130_fd_pr/pfet3_01v8_hvt.sym} 690 -1100 3 1 {name=MP34
W=1.26
L=0.15
body=vdd
nf=1
mult=1
ad="'int((nf+1)/2) * W/nf * 0.29'" 
pd="'2*int((nf+1)/2) * (W/nf + 0.29)'"
as="'int((nf+2)/2) * W/nf * 0.29'" 
ps="'2*int((nf+2)/2) * (W/nf + 0.29)'"
nrd="'0.29 / W'" nrs="'0.29 / W'"
sa=0 sb=0 sd=0
model=pfet_01v8_hvt
spiceprefix=X
}
C {sky130_fd_pr/pfet3_01v8_hvt.sym} 770 -1100 3 1 {name=MP44
W=1.26
L=0.15
body=vdd
nf=1
mult=1
ad="'int((nf+1)/2) * W/nf * 0.29'" 
pd="'2*int((nf+1)/2) * (W/nf + 0.29)'"
as="'int((nf+2)/2) * W/nf * 0.29'" 
ps="'2*int((nf+2)/2) * (W/nf + 0.29)'"
nrd="'0.29 / W'" nrs="'0.29 / W'"
sa=0 sb=0 sd=0
model=pfet_01v8_hvt
spiceprefix=X
}
C {ipin.sym} 1330 -1290 0 0 {name=p31 lab=b[1]}
C {ipin.sym} 1330 -1270 0 0 {name=p32 lab=b[0]}
C {lab_pin.sym} 1360 -1200 0 0 {name=p33 sig_type=std_logic lab=b[2:0]}
C {bus_connect_nolab.sym} 1360 -1300 0 1 {name=r15}
C {bus_connect_nolab.sym} 1360 -1280 0 1 {name=r16}
C {bus_connect_nolab.sym} 1360 -1260 0 1 {name=r17}
C {copyright.sym} 0 10 0 0 {name=s1 place=header value="* Copyright (c) Eric Fogleman 2025 
* SPDX-License-Identifier: Apache-2.0"}
C {lab_wire.sym} 730 -970 0 0 {name=p34 sig_type=std_logic lab=mp2_2g}
C {lab_wire.sym} 550 -970 0 0 {name=p35 sig_type=std_logic lab=mp2_1g}
C {lab_wire.sym} 370 -970 0 0 {name=p36 sig_type=std_logic lab=mp2_1p5g}
C {sky130_fd_pr/res_xhigh_po_0p69.sym} 520 -700 0 0 {name=R1
L=8.97
model=res_xhigh_po_0p69
spiceprefix=X
mult=1}
C {sky130_fd_pr/res_xhigh_po_0p69.sym} 520 -630 0 0 {name=R2
L=8.97
model=res_xhigh_po_0p69
spiceprefix=X
mult=1}
C {sky130_fd_pr/res_xhigh_po_0p69.sym} 670 -630 0 0 {name=R3
L=8.97
model=res_xhigh_po_0p69
spiceprefix=X
mult=1}
C {sky130_fd_pr/res_xhigh_po_0p69.sym} 670 -700 0 0 {name=R4
L=8.97
model=res_xhigh_po_0p69
spiceprefix=X
mult=1}
C {sky130_fd_pr/pfet3_01v8_lvt.sym} 1060 -800 0 0 {name=MP4C
W=1.44
L=0.42
body=vdd
nf=2
mult=1
ad="'int((nf+1)/2) * W/nf * 0.29'" 
pd="'2*int((nf+1)/2) * (W/nf + 0.29)'"
as="'int((nf+2)/2) * W/nf * 0.29'" 
ps="'2*int((nf+2)/2) * (W/nf + 0.29)'"
nrd="'0.29 / W'" nrs="'0.29 / W'"
sa=0 sb=0 sd=0
model=pfet_01v8_lvt
spiceprefix=X
}
C {sky130_fd_pr/pfet3_01v8_lvt.sym} 1060 -930 0 0 {name=MP4[2:0]
W=0.72
L=1.44
body=vdd
nf=1
mult=1
ad="'int((nf+1)/2) * W/nf * 0.29'" 
pd="'2*int((nf+1)/2) * (W/nf + 0.29)'"
as="'int((nf+2)/2) * W/nf * 0.29'" 
ps="'2*int((nf+2)/2) * (W/nf + 0.29)'"
nrd="'0.29 / W'" nrs="'0.29 / W'"
sa=0 sb=0 sd=0
model=pfet_01v8_lvt
spiceprefix=X
}
C {sky130_fd_pr/nfet3_01v8.sym} 1060 -250 0 0 {name=MN4[0]
W=0.72
L=1.44
body=gnd
nf=1
mult=1
ad="'int((nf+1)/2) * W/nf * 0.29'" 
pd="'2*int((nf+1)/2) * (W/nf + 0.29)'"
as="'int((nf+2)/2) * W/nf * 0.29'" 
ps="'2*int((nf+2)/2) * (W/nf + 0.29)'"
nrd="'0.29 / W'" nrs="'0.29 / W'"
sa=0 sb=0 sd=0
model=nfet_01v8
spiceprefix=X
}
C {sky130_fd_pr/nfet3_01v8.sym} 1060 -320 0 0 {name=MN4[1]
W=0.72
L=1.44
body=gnd
nf=1
mult=1
ad="'int((nf+1)/2) * W/nf * 0.29'" 
pd="'2*int((nf+1)/2) * (W/nf + 0.29)'"
as="'int((nf+2)/2) * W/nf * 0.29'" 
ps="'2*int((nf+2)/2) * (W/nf + 0.29)'"
nrd="'0.29 / W'" nrs="'0.29 / W'"
sa=0 sb=0 sd=0
model=nfet_01v8
spiceprefix=X
}
C {sky130_fd_pr/nfet3_01v8.sym} 1060 -390 0 0 {name=MN4[2]
W=0.72
L=1.44
body=gnd
nf=1
mult=1
ad="'int((nf+1)/2) * W/nf * 0.29'" 
pd="'2*int((nf+1)/2) * (W/nf + 0.29)'"
as="'int((nf+2)/2) * W/nf * 0.29'" 
ps="'2*int((nf+2)/2) * (W/nf + 0.29)'"
nrd="'0.29 / W'" nrs="'0.29 / W'"
sa=0 sb=0 sd=0
model=nfet_01v8
spiceprefix=X
}
C {sky130_fd_pr/nfet3_01v8.sym} 1060 -460 0 0 {name=MN4[3]
W=0.72
L=1.44
body=gnd
nf=1
mult=1
ad="'int((nf+1)/2) * W/nf * 0.29'" 
pd="'2*int((nf+1)/2) * (W/nf + 0.29)'"
as="'int((nf+2)/2) * W/nf * 0.29'" 
ps="'2*int((nf+2)/2) * (W/nf + 0.29)'"
nrd="'0.29 / W'" nrs="'0.29 / W'"
sa=0 sb=0 sd=0
model=nfet_01v8
spiceprefix=X
}
C {sky130_fd_pr/nfet3_01v8.sym} 1060 -530 0 0 {name=MN4[4]
W=0.72
L=1.44
body=gnd
nf=1
mult=1
ad="'int((nf+1)/2) * W/nf * 0.29'" 
pd="'2*int((nf+1)/2) * (W/nf + 0.29)'"
as="'int((nf+2)/2) * W/nf * 0.29'" 
ps="'2*int((nf+2)/2) * (W/nf + 0.29)'"
nrd="'0.29 / W'" nrs="'0.29 / W'"
sa=0 sb=0 sd=0
model=nfet_01v8
spiceprefix=X
}
C {sky130_fd_pr/pfet3_01v8_lvt.sym} 1830 -930 0 0 {name=MP26[2:0]
W=0.72
L=1.44
body=vdd
nf=1
mult=1
ad="'int((nf+1)/2) * W/nf * 0.29'" 
pd="'2*int((nf+1)/2) * (W/nf + 0.29)'"
as="'int((nf+2)/2) * W/nf * 0.29'" 
ps="'2*int((nf+2)/2) * (W/nf + 0.29)'"
nrd="'0.29 / W'" nrs="'0.29 / W'"
sa=0 sb=0 sd=0
model=pfet_01v8_lvt
spiceprefix=X
}
C {sky130_fd_pr/nfet3_01v8.sym} 1830 -200 0 0 {name=MN25
W=0.72
L=1.44
body=gnd
nf=1
mult=1
ad="'int((nf+1)/2) * W/nf * 0.29'" 
pd="'2*int((nf+1)/2) * (W/nf + 0.29)'"
as="'int((nf+2)/2) * W/nf * 0.29'" 
ps="'2*int((nf+2)/2) * (W/nf + 0.29)'"
nrd="'0.29 / W'" nrs="'0.29 / W'"
sa=0 sb=0 sd=0
model=nfet_01v8
spiceprefix=X
}
C {sky130_fd_pr/nfet3_01v8.sym} 1830 -330 0 0 {name=MN25C
W=0.72
L=0.36
body=gnd
nf=1
mult=1
ad="'int((nf+1)/2) * W/nf * 0.29'" 
pd="'2*int((nf+1)/2) * (W/nf + 0.29)'"
as="'int((nf+2)/2) * W/nf * 0.29'" 
ps="'2*int((nf+2)/2) * (W/nf + 0.29)'"
nrd="'0.29 / W'" nrs="'0.29 / W'"
sa=0 sb=0 sd=0
model=nfet_01v8
spiceprefix=X
}
C {lab_wire.sym} 1480 -800 0 0 {name=p25 sig_type=std_logic lab=mp20d}
C {sky130_fd_pr/nfet3_01v8.sym} 1060 -600 0 0 {name=MN4[5]
W=0.72
L=1.44
body=gnd
nf=1
mult=1
ad="'int((nf+1)/2) * W/nf * 0.29'" 
pd="'2*int((nf+1)/2) * (W/nf + 0.29)'"
as="'int((nf+2)/2) * W/nf * 0.29'" 
ps="'2*int((nf+2)/2) * (W/nf + 0.29)'"
nrd="'0.29 / W'" nrs="'0.29 / W'"
sa=0 sb=0 sd=0
model=nfet_01v8
spiceprefix=X
}
C {sky130_fd_pr/nfet3_01v8.sym} 1970 -220 1 0 {name=MNCAP1[9:0]
W=7.92
L=1.98
body=gnd
nf=2
mult=1
ad="'int((nf+1)/2) * W/nf * 0.29'" 
pd="'2*int((nf+1)/2) * (W/nf + 0.29)'"
as="'int((nf+2)/2) * W/nf * 0.29'" 
ps="'2*int((nf+2)/2) * (W/nf + 0.29)'"
nrd="'0.29 / W'" nrs="'0.29 / W'"
sa=0 sb=0 sd=0
model=nfet_01v8
spiceprefix=X
}
C {sky130_fd_pr/nfet3_01v8.sym} 2410 -270 1 0 {name=MNCAP2
W=7.92
L=1.98
body=gnd
nf=2
mult=1
ad="'int((nf+1)/2) * W/nf * 0.29'" 
pd="'2*int((nf+1)/2) * (W/nf + 0.29)'"
as="'int((nf+2)/2) * W/nf * 0.29'" 
ps="'2*int((nf+2)/2) * (W/nf + 0.29)'"
nrd="'0.29 / W'" nrs="'0.29 / W'"
sa=0 sb=0 sd=0
model=nfet_01v8
spiceprefix=X
}
C {ipin.sym} 2750 -780 0 1 {name=p38 lab=vc2}
C {sky130_fd_pr/pfet3_01v8_lvt.sym} 1830 -690 0 0 {name=MP1
W=0.72
L=0.42
body=vdd
nf=1
mult=1
ad="'int((nf+1)/2) * W/nf * 0.29'" 
pd="'2*int((nf+1)/2) * (W/nf + 0.29)'"
as="'int((nf+2)/2) * W/nf * 0.29'" 
ps="'2*int((nf+2)/2) * (W/nf + 0.29)'"
nrd="'0.29 / W'" nrs="'0.29 / W'"
sa=0 sb=0 sd=0
model=pfet_01v8_lvt
spiceprefix=X
}
C {sky130_fd_pr/pfet3_01v8_lvt.sym} 1830 -630 0 0 {name=MP2
W=0.72
L=0.42
body=vdd
nf=1
mult=1
ad="'int((nf+1)/2) * W/nf * 0.29'" 
pd="'2*int((nf+1)/2) * (W/nf + 0.29)'"
as="'int((nf+2)/2) * W/nf * 0.29'" 
ps="'2*int((nf+2)/2) * (W/nf + 0.29)'"
nrd="'0.29 / W'" nrs="'0.29 / W'"
sa=0 sb=0 sd=0
model=pfet_01v8_lvt
spiceprefix=X
}
C {sky130_fd_pr/pfet3_01v8_lvt.sym} 1830 -570 0 0 {name=MP3
W=0.72
L=0.42
body=vdd
nf=1
mult=1
ad="'int((nf+1)/2) * W/nf * 0.29'" 
pd="'2*int((nf+1)/2) * (W/nf + 0.29)'"
as="'int((nf+2)/2) * W/nf * 0.29'" 
ps="'2*int((nf+2)/2) * (W/nf + 0.29)'"
nrd="'0.29 / W'" nrs="'0.29 / W'"
sa=0 sb=0 sd=0
model=pfet_01v8_lvt
spiceprefix=X
}
C {sky130_fd_pr/pfet3_01v8_lvt.sym} 1830 -510 0 0 {name=MP4
W=0.72
L=0.42
body=vdd
nf=1
mult=1
ad="'int((nf+1)/2) * W/nf * 0.29'" 
pd="'2*int((nf+1)/2) * (W/nf + 0.29)'"
as="'int((nf+2)/2) * W/nf * 0.29'" 
ps="'2*int((nf+2)/2) * (W/nf + 0.29)'"
nrd="'0.29 / W'" nrs="'0.29 / W'"
sa=0 sb=0 sd=0
model=pfet_01v8_lvt
spiceprefix=X
}
C {sky130_fd_pr/pfet3_01v8_lvt.sym} 1830 -450 0 0 {name=MP5
W=0.72
L=0.42
body=vdd
nf=1
mult=1
ad="'int((nf+1)/2) * W/nf * 0.29'" 
pd="'2*int((nf+1)/2) * (W/nf + 0.29)'"
as="'int((nf+2)/2) * W/nf * 0.29'" 
ps="'2*int((nf+2)/2) * (W/nf + 0.29)'"
nrd="'0.29 / W'" nrs="'0.29 / W'"
sa=0 sb=0 sd=0
model=pfet_01v8_lvt
spiceprefix=X
}
C {sky130_fd_pr/pfet3_01v8_lvt.sym} 1590 -610 0 0 {name=MP21PC
W=0.72
L=0.42
body=vdd
nf=1
mult=1
ad="'int((nf+1)/2) * W/nf * 0.29'" 
pd="'2*int((nf+1)/2) * (W/nf + 0.29)'"
as="'int((nf+2)/2) * W/nf * 0.29'" 
ps="'2*int((nf+2)/2) * (W/nf + 0.29)'"
nrd="'0.29 / W'" nrs="'0.29 / W'"
sa=0 sb=0 sd=0
model=pfet_01v8_lvt
spiceprefix=X
}
C {sky130_fd_pr/pfet3_01v8_lvt.sym} 1390 -610 0 1 {name=MP21NC
W=0.72
L=0.42
body=vdd
nf=1
mult=1
ad="'int((nf+1)/2) * W/nf * 0.29'" 
pd="'2*int((nf+1)/2) * (W/nf + 0.29)'"
as="'int((nf+2)/2) * W/nf * 0.29'" 
ps="'2*int((nf+2)/2) * (W/nf + 0.29)'"
nrd="'0.29 / W'" nrs="'0.29 / W'"
sa=0 sb=0 sd=0
model=pfet_01v8_lvt
spiceprefix=X
}
C {lab_wire.sym} 1520 -610 0 0 {name=p7 sig_type=std_logic lab=mp21cg
}
C {lab_wire.sym} 1610 -670 0 0 {name=p8 sig_type=std_logic lab=mp21pd}
C {lab_wire.sym} 1370 -670 0 0 {name=p29 sig_type=std_logic lab=mp21nd}
